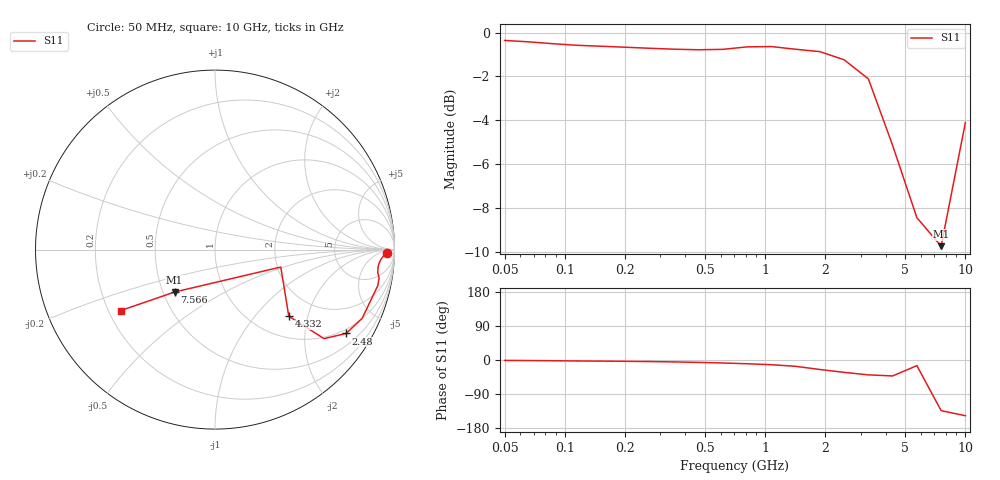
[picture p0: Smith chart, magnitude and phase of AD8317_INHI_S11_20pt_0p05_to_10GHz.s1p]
! AD8317 INHI/INLO input model, 0.05-10 GHz
! Sources: AD8317 Rev.D pp.3-4 impedance table + p.9 Figure 15 approximation
! INLO is RF common (AC-coupled to ground), modeled implicitly in single-ended S11 at INHI.
# GHZ S RI R 50
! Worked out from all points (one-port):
!   20 points, 50 MHz to 10 GHz, reference 50 ohm
!   lowest |S11| = -9.7 dB at 7.566 GHz (marker M1), VSWR 1.97, Z = 28.7 - j15.2 ohm
!   |S11| at or under -10 dB: nowhere
!   S11 on the Smith chart (normalised r, x): 50 MHz: 40, -18; 2.48 GHz: 0.85, -3.21; 4.332 GHz: 1.43, -1.53; 7.566 GHz: 0.57, -0.30; 10 GHz: 0.25, -0.28
0.05  0.9591 -0.018
0.066081  0.9521 -0.0233
0.087334  0.9425 -0.0321
0.115423  0.9342 -0.0414
0.152545  0.9293 -0.0478
0.201606  0.924 -0.056
0.266447  0.9183 -0.0666
0.352142  0.9127 -0.0808
0.465398  0.9082 -0.0999
0.61508  0.907 -0.1256
0.812902  0.9138 -0.1593
1.074349  0.9074 -0.1997
1.419882  0.8776 -0.2626
1.876545  0.8196 -0.3832
2.480081  0.7303 -0.4672
3.277726  0.6076 -0.4961
4.33191  0.4111 -0.371
5.725143  0.3665 -0.0972
7.566467  -0.2254 -0.2365
10  -0.5239 -0.3393
